VERSION 5.7 ;
  NOWIREEXTENSIONATPIN ON ;
  DIVIDERCHAR "/" ;
  BUSBITCHARS "[]" ;
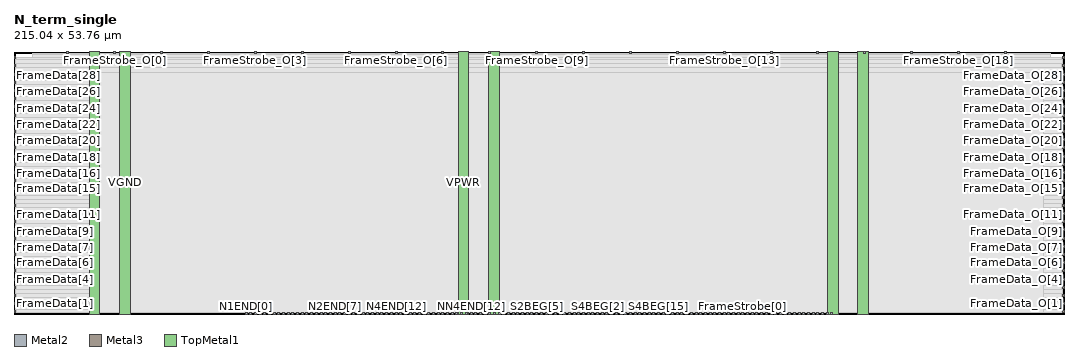
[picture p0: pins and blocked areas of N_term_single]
MACRO N_term_single
  CLASS BLOCK ;
  FOREIGN N_term_single ;
  ORIGIN 0.000 0.000 ;
  SIZE 215.040 BY 53.760 ;
  PIN Ci
    DIRECTION INPUT ;
    USE SIGNAL ;
    PORT
      LAYER Metal2 ;
        RECT 97.240 0.000 97.640 0.400 ;
    END
  END Ci
  PIN FrameData[0]
    DIRECTION INPUT ;
    USE SIGNAL ;
    ANTENNAGATEAREA 0.180700 ;
    PORT
      LAYER Metal3 ;
        RECT 0.000 0.220 0.400 0.620 ;
    END
  END FrameData[0]
  PIN FrameData[10]
    DIRECTION INPUT ;
    USE SIGNAL ;
    ANTENNAGATEAREA 0.180700 ;
    PORT
      LAYER Metal3 ;
        RECT 0.000 17.020 0.400 17.420 ;
    END
  END FrameData[10]
  PIN FrameData[11]
    DIRECTION INPUT ;
    USE SIGNAL ;
    ANTENNAGATEAREA 0.180700 ;
    PORT
      LAYER Metal3 ;
        RECT 0.000 18.700 0.400 19.100 ;
    END
  END FrameData[11]
  PIN FrameData[12]
    DIRECTION INPUT ;
    USE SIGNAL ;
    ANTENNAGATEAREA 0.180700 ;
    PORT
      LAYER Metal3 ;
        RECT 0.000 20.380 0.400 20.780 ;
    END
  END FrameData[12]
  PIN FrameData[13]
    DIRECTION INPUT ;
    USE SIGNAL ;
    ANTENNAGATEAREA 0.180700 ;
    PORT
      LAYER Metal3 ;
        RECT 0.000 22.060 0.400 22.460 ;
    END
  END FrameData[13]
  PIN FrameData[14]
    DIRECTION INPUT ;
    USE SIGNAL ;
    ANTENNAGATEAREA 0.180700 ;
    PORT
      LAYER Metal3 ;
        RECT 0.000 23.740 0.400 24.140 ;
    END
  END FrameData[14]
  PIN FrameData[15]
    DIRECTION INPUT ;
    USE SIGNAL ;
    ANTENNAGATEAREA 0.180700 ;
    PORT
      LAYER Metal3 ;
        RECT 0.000 25.420 0.400 25.820 ;
    END
  END FrameData[15]
  PIN FrameData[16]
    DIRECTION INPUT ;
    USE SIGNAL ;
    ANTENNAGATEAREA 0.180700 ;
    PORT
      LAYER Metal3 ;
        RECT 0.000 27.100 0.400 27.500 ;
    END
  END FrameData[16]
  PIN FrameData[17]
    DIRECTION INPUT ;
    USE SIGNAL ;
    ANTENNAGATEAREA 0.180700 ;
    PORT
      LAYER Metal3 ;
        RECT 0.000 28.780 0.400 29.180 ;
    END
  END FrameData[17]
  PIN FrameData[18]
    DIRECTION INPUT ;
    USE SIGNAL ;
    ANTENNAGATEAREA 0.180700 ;
    PORT
      LAYER Metal3 ;
        RECT 0.000 30.460 0.400 30.860 ;
    END
  END FrameData[18]
  PIN FrameData[19]
    DIRECTION INPUT ;
    USE SIGNAL ;
    ANTENNAGATEAREA 0.180700 ;
    PORT
      LAYER Metal3 ;
        RECT 0.000 32.140 0.400 32.540 ;
    END
  END FrameData[19]
  PIN FrameData[1]
    DIRECTION INPUT ;
    USE SIGNAL ;
    ANTENNAGATEAREA 0.180700 ;
    PORT
      LAYER Metal3 ;
        RECT 0.000 1.900 0.400 2.300 ;
    END
  END FrameData[1]
  PIN FrameData[20]
    DIRECTION INPUT ;
    USE SIGNAL ;
    ANTENNAGATEAREA 0.180700 ;
    PORT
      LAYER Metal3 ;
        RECT 0.000 33.820 0.400 34.220 ;
    END
  END FrameData[20]
  PIN FrameData[21]
    DIRECTION INPUT ;
    USE SIGNAL ;
    ANTENNAGATEAREA 0.180700 ;
    PORT
      LAYER Metal3 ;
        RECT 0.000 35.500 0.400 35.900 ;
    END
  END FrameData[21]
  PIN FrameData[22]
    DIRECTION INPUT ;
    USE SIGNAL ;
    ANTENNAGATEAREA 0.180700 ;
    PORT
      LAYER Metal3 ;
        RECT 0.000 37.180 0.400 37.580 ;
    END
  END FrameData[22]
  PIN FrameData[23]
    DIRECTION INPUT ;
    USE SIGNAL ;
    ANTENNAGATEAREA 0.180700 ;
    PORT
      LAYER Metal3 ;
        RECT 0.000 38.860 0.400 39.260 ;
    END
  END FrameData[23]
  PIN FrameData[24]
    DIRECTION INPUT ;
    USE SIGNAL ;
    ANTENNAGATEAREA 0.180700 ;
    PORT
      LAYER Metal3 ;
        RECT 0.000 40.540 0.400 40.940 ;
    END
  END FrameData[24]
  PIN FrameData[25]
    DIRECTION INPUT ;
    USE SIGNAL ;
    ANTENNAGATEAREA 0.180700 ;
    PORT
      LAYER Metal3 ;
        RECT 0.000 42.220 0.400 42.620 ;
    END
  END FrameData[25]
  PIN FrameData[26]
    DIRECTION INPUT ;
    USE SIGNAL ;
    ANTENNAGATEAREA 0.180700 ;
    PORT
      LAYER Metal3 ;
        RECT 0.000 43.900 0.400 44.300 ;
    END
  END FrameData[26]
  PIN FrameData[27]
    DIRECTION INPUT ;
    USE SIGNAL ;
    ANTENNAGATEAREA 0.180700 ;
    PORT
      LAYER Metal3 ;
        RECT 0.000 45.580 0.400 45.980 ;
    END
  END FrameData[27]
  PIN FrameData[28]
    DIRECTION INPUT ;
    USE SIGNAL ;
    ANTENNAGATEAREA 0.180700 ;
    PORT
      LAYER Metal3 ;
        RECT 0.000 47.260 0.400 47.660 ;
    END
  END FrameData[28]
  PIN FrameData[29]
    DIRECTION INPUT ;
    USE SIGNAL ;
    ANTENNAGATEAREA 0.180700 ;
    PORT
      LAYER Metal3 ;
        RECT 0.000 48.940 0.400 49.340 ;
    END
  END FrameData[29]
  PIN FrameData[2]
    DIRECTION INPUT ;
    USE SIGNAL ;
    ANTENNAGATEAREA 0.180700 ;
    PORT
      LAYER Metal3 ;
        RECT 0.000 3.580 0.400 3.980 ;
    END
  END FrameData[2]
  PIN FrameData[30]
    DIRECTION INPUT ;
    USE SIGNAL ;
    ANTENNAGATEAREA 0.180700 ;
    PORT
      LAYER Metal3 ;
        RECT 0.000 50.620 0.400 51.020 ;
    END
  END FrameData[30]
  PIN FrameData[31]
    DIRECTION INPUT ;
    USE SIGNAL ;
    ANTENNAGATEAREA 0.180700 ;
    PORT
      LAYER Metal3 ;
        RECT 0.000 52.300 0.400 52.700 ;
    END
  END FrameData[31]
  PIN FrameData[3]
    DIRECTION INPUT ;
    USE SIGNAL ;
    ANTENNAGATEAREA 0.180700 ;
    PORT
      LAYER Metal3 ;
        RECT 0.000 5.260 0.400 5.660 ;
    END
  END FrameData[3]
  PIN FrameData[4]
    DIRECTION INPUT ;
    USE SIGNAL ;
    ANTENNAGATEAREA 0.180700 ;
    PORT
      LAYER Metal3 ;
        RECT 0.000 6.940 0.400 7.340 ;
    END
  END FrameData[4]
  PIN FrameData[5]
    DIRECTION INPUT ;
    USE SIGNAL ;
    ANTENNAGATEAREA 0.180700 ;
    PORT
      LAYER Metal3 ;
        RECT 0.000 8.620 0.400 9.020 ;
    END
  END FrameData[5]
  PIN FrameData[6]
    DIRECTION INPUT ;
    USE SIGNAL ;
    ANTENNAGATEAREA 0.180700 ;
    PORT
      LAYER Metal3 ;
        RECT 0.000 10.300 0.400 10.700 ;
    END
  END FrameData[6]
  PIN FrameData[7]
    DIRECTION INPUT ;
    USE SIGNAL ;
    ANTENNAGATEAREA 0.180700 ;
    PORT
      LAYER Metal3 ;
        RECT 0.000 11.980 0.400 12.380 ;
    END
  END FrameData[7]
  PIN FrameData[8]
    DIRECTION INPUT ;
    USE SIGNAL ;
    ANTENNAGATEAREA 0.180700 ;
    PORT
      LAYER Metal3 ;
        RECT 0.000 13.660 0.400 14.060 ;
    END
  END FrameData[8]
  PIN FrameData[9]
    DIRECTION INPUT ;
    USE SIGNAL ;
    ANTENNAGATEAREA 0.180700 ;
    PORT
      LAYER Metal3 ;
        RECT 0.000 15.340 0.400 15.740 ;
    END
  END FrameData[9]
  PIN FrameData_O[0]
    DIRECTION OUTPUT ;
    USE SIGNAL ;
    ANTENNADIFFAREA 0.708600 ;
    PORT
      LAYER Metal3 ;
        RECT 214.640 0.220 215.040 0.620 ;
    END
  END FrameData_O[0]
  PIN FrameData_O[10]
    DIRECTION OUTPUT ;
    USE SIGNAL ;
    ANTENNADIFFAREA 0.708600 ;
    PORT
      LAYER Metal3 ;
        RECT 214.640 17.020 215.040 17.420 ;
    END
  END FrameData_O[10]
  PIN FrameData_O[11]
    DIRECTION OUTPUT ;
    USE SIGNAL ;
    ANTENNADIFFAREA 0.708600 ;
    PORT
      LAYER Metal3 ;
        RECT 214.640 18.700 215.040 19.100 ;
    END
  END FrameData_O[11]
  PIN FrameData_O[12]
    DIRECTION OUTPUT ;
    USE SIGNAL ;
    ANTENNADIFFAREA 0.708600 ;
    PORT
      LAYER Metal3 ;
        RECT 214.640 20.380 215.040 20.780 ;
    END
  END FrameData_O[12]
  PIN FrameData_O[13]
    DIRECTION OUTPUT ;
    USE SIGNAL ;
    ANTENNADIFFAREA 0.708600 ;
    PORT
      LAYER Metal3 ;
        RECT 214.640 22.060 215.040 22.460 ;
    END
  END FrameData_O[13]
  PIN FrameData_O[14]
    DIRECTION OUTPUT ;
    USE SIGNAL ;
    ANTENNADIFFAREA 0.708600 ;
    PORT
      LAYER Metal3 ;
        RECT 214.640 23.740 215.040 24.140 ;
    END
  END FrameData_O[14]
  PIN FrameData_O[15]
    DIRECTION OUTPUT ;
    USE SIGNAL ;
    ANTENNADIFFAREA 0.708600 ;
    PORT
      LAYER Metal3 ;
        RECT 214.640 25.420 215.040 25.820 ;
    END
  END FrameData_O[15]
  PIN FrameData_O[16]
    DIRECTION OUTPUT ;
    USE SIGNAL ;
    ANTENNADIFFAREA 0.708600 ;
    PORT
      LAYER Metal3 ;
        RECT 214.640 27.100 215.040 27.500 ;
    END
  END FrameData_O[16]
  PIN FrameData_O[17]
    DIRECTION OUTPUT ;
    USE SIGNAL ;
    ANTENNADIFFAREA 0.708600 ;
    PORT
      LAYER Metal3 ;
        RECT 214.640 28.780 215.040 29.180 ;
    END
  END FrameData_O[17]
  PIN FrameData_O[18]
    DIRECTION OUTPUT ;
    USE SIGNAL ;
    ANTENNADIFFAREA 0.708600 ;
    PORT
      LAYER Metal3 ;
        RECT 214.640 30.460 215.040 30.860 ;
    END
  END FrameData_O[18]
  PIN FrameData_O[19]
    DIRECTION OUTPUT ;
    USE SIGNAL ;
    ANTENNADIFFAREA 0.708600 ;
    PORT
      LAYER Metal3 ;
        RECT 214.640 32.140 215.040 32.540 ;
    END
  END FrameData_O[19]
  PIN FrameData_O[1]
    DIRECTION OUTPUT ;
    USE SIGNAL ;
    ANTENNADIFFAREA 0.708600 ;
    PORT
      LAYER Metal3 ;
        RECT 214.640 1.900 215.040 2.300 ;
    END
  END FrameData_O[1]
  PIN FrameData_O[20]
    DIRECTION OUTPUT ;
    USE SIGNAL ;
    ANTENNADIFFAREA 0.708600 ;
    PORT
      LAYER Metal3 ;
        RECT 214.640 33.820 215.040 34.220 ;
    END
  END FrameData_O[20]
  PIN FrameData_O[21]
    DIRECTION OUTPUT ;
    USE SIGNAL ;
    ANTENNADIFFAREA 0.708600 ;
    PORT
      LAYER Metal3 ;
        RECT 214.640 35.500 215.040 35.900 ;
    END
  END FrameData_O[21]
  PIN FrameData_O[22]
    DIRECTION OUTPUT ;
    USE SIGNAL ;
    ANTENNADIFFAREA 0.708600 ;
    PORT
      LAYER Metal3 ;
        RECT 214.640 37.180 215.040 37.580 ;
    END
  END FrameData_O[22]
  PIN FrameData_O[23]
    DIRECTION OUTPUT ;
    USE SIGNAL ;
    ANTENNADIFFAREA 0.708600 ;
    PORT
      LAYER Metal3 ;
        RECT 214.640 38.860 215.040 39.260 ;
    END
  END FrameData_O[23]
  PIN FrameData_O[24]
    DIRECTION OUTPUT ;
    USE SIGNAL ;
    ANTENNADIFFAREA 0.708600 ;
    PORT
      LAYER Metal3 ;
        RECT 214.640 40.540 215.040 40.940 ;
    END
  END FrameData_O[24]
  PIN FrameData_O[25]
    DIRECTION OUTPUT ;
    USE SIGNAL ;
    ANTENNADIFFAREA 0.708600 ;
    PORT
      LAYER Metal3 ;
        RECT 214.640 42.220 215.040 42.620 ;
    END
  END FrameData_O[25]
  PIN FrameData_O[26]
    DIRECTION OUTPUT ;
    USE SIGNAL ;
    ANTENNADIFFAREA 0.708600 ;
    PORT
      LAYER Metal3 ;
        RECT 214.640 43.900 215.040 44.300 ;
    END
  END FrameData_O[26]
  PIN FrameData_O[27]
    DIRECTION OUTPUT ;
    USE SIGNAL ;
    ANTENNADIFFAREA 0.708600 ;
    PORT
      LAYER Metal3 ;
        RECT 214.640 45.580 215.040 45.980 ;
    END
  END FrameData_O[27]
  PIN FrameData_O[28]
    DIRECTION OUTPUT ;
    USE SIGNAL ;
    ANTENNADIFFAREA 0.708600 ;
    PORT
      LAYER Metal3 ;
        RECT 214.640 47.260 215.040 47.660 ;
    END
  END FrameData_O[28]
  PIN FrameData_O[29]
    DIRECTION OUTPUT ;
    USE SIGNAL ;
    ANTENNADIFFAREA 0.708600 ;
    PORT
      LAYER Metal3 ;
        RECT 214.640 48.940 215.040 49.340 ;
    END
  END FrameData_O[29]
  PIN FrameData_O[2]
    DIRECTION OUTPUT ;
    USE SIGNAL ;
    ANTENNADIFFAREA 0.708600 ;
    PORT
      LAYER Metal3 ;
        RECT 214.640 3.580 215.040 3.980 ;
    END
  END FrameData_O[2]
  PIN FrameData_O[30]
    DIRECTION OUTPUT ;
    USE SIGNAL ;
    ANTENNADIFFAREA 0.708600 ;
    PORT
      LAYER Metal3 ;
        RECT 214.640 50.620 215.040 51.020 ;
    END
  END FrameData_O[30]
  PIN FrameData_O[31]
    DIRECTION OUTPUT ;
    USE SIGNAL ;
    ANTENNADIFFAREA 0.708600 ;
    PORT
      LAYER Metal3 ;
        RECT 214.640 52.300 215.040 52.700 ;
    END
  END FrameData_O[31]
  PIN FrameData_O[3]
    DIRECTION OUTPUT ;
    USE SIGNAL ;
    ANTENNADIFFAREA 0.708600 ;
    PORT
      LAYER Metal3 ;
        RECT 214.640 5.260 215.040 5.660 ;
    END
  END FrameData_O[3]
  PIN FrameData_O[4]
    DIRECTION OUTPUT ;
    USE SIGNAL ;
    ANTENNADIFFAREA 0.708600 ;
    PORT
      LAYER Metal3 ;
        RECT 214.640 6.940 215.040 7.340 ;
    END
  END FrameData_O[4]
  PIN FrameData_O[5]
    DIRECTION OUTPUT ;
    USE SIGNAL ;
    ANTENNADIFFAREA 0.708600 ;
    PORT
      LAYER Metal3 ;
        RECT 214.640 8.620 215.040 9.020 ;
    END
  END FrameData_O[5]
  PIN FrameData_O[6]
    DIRECTION OUTPUT ;
    USE SIGNAL ;
    ANTENNADIFFAREA 0.708600 ;
    PORT
      LAYER Metal3 ;
        RECT 214.640 10.300 215.040 10.700 ;
    END
  END FrameData_O[6]
  PIN FrameData_O[7]
    DIRECTION OUTPUT ;
    USE SIGNAL ;
    ANTENNADIFFAREA 0.708600 ;
    PORT
      LAYER Metal3 ;
        RECT 214.640 11.980 215.040 12.380 ;
    END
  END FrameData_O[7]
  PIN FrameData_O[8]
    DIRECTION OUTPUT ;
    USE SIGNAL ;
    ANTENNADIFFAREA 0.708600 ;
    PORT
      LAYER Metal3 ;
        RECT 214.640 13.660 215.040 14.060 ;
    END
  END FrameData_O[8]
  PIN FrameData_O[9]
    DIRECTION OUTPUT ;
    USE SIGNAL ;
    ANTENNADIFFAREA 0.708600 ;
    PORT
      LAYER Metal3 ;
        RECT 214.640 15.340 215.040 15.740 ;
    END
  END FrameData_O[9]
  PIN FrameStrobe[0]
    DIRECTION INPUT ;
    USE SIGNAL ;
    ANTENNAGATEAREA 0.180700 ;
    PORT
      LAYER Metal2 ;
        RECT 149.080 0.000 149.480 0.400 ;
    END
  END FrameStrobe[0]
  PIN FrameStrobe[10]
    DIRECTION INPUT ;
    USE SIGNAL ;
    ANTENNAGATEAREA 0.180700 ;
    PORT
      LAYER Metal2 ;
        RECT 158.680 0.000 159.080 0.400 ;
    END
  END FrameStrobe[10]
  PIN FrameStrobe[11]
    DIRECTION INPUT ;
    USE SIGNAL ;
    ANTENNAGATEAREA 0.180700 ;
    PORT
      LAYER Metal2 ;
        RECT 159.640 0.000 160.040 0.400 ;
    END
  END FrameStrobe[11]
  PIN FrameStrobe[12]
    DIRECTION INPUT ;
    USE SIGNAL ;
    ANTENNAGATEAREA 0.180700 ;
    PORT
      LAYER Metal2 ;
        RECT 160.600 0.000 161.000 0.400 ;
    END
  END FrameStrobe[12]
  PIN FrameStrobe[13]
    DIRECTION INPUT ;
    USE SIGNAL ;
    ANTENNAGATEAREA 0.180700 ;
    PORT
      LAYER Metal2 ;
        RECT 161.560 0.000 161.960 0.400 ;
    END
  END FrameStrobe[13]
  PIN FrameStrobe[14]
    DIRECTION INPUT ;
    USE SIGNAL ;
    ANTENNAGATEAREA 0.180700 ;
    PORT
      LAYER Metal2 ;
        RECT 162.520 0.000 162.920 0.400 ;
    END
  END FrameStrobe[14]
  PIN FrameStrobe[15]
    DIRECTION INPUT ;
    USE SIGNAL ;
    ANTENNAGATEAREA 0.180700 ;
    PORT
      LAYER Metal2 ;
        RECT 163.480 0.000 163.880 0.400 ;
    END
  END FrameStrobe[15]
  PIN FrameStrobe[16]
    DIRECTION INPUT ;
    USE SIGNAL ;
    ANTENNAGATEAREA 0.180700 ;
    PORT
      LAYER Metal2 ;
        RECT 164.440 0.000 164.840 0.400 ;
    END
  END FrameStrobe[16]
  PIN FrameStrobe[17]
    DIRECTION INPUT ;
    USE SIGNAL ;
    ANTENNAGATEAREA 0.180700 ;
    PORT
      LAYER Metal2 ;
        RECT 165.400 0.000 165.800 0.400 ;
    END
  END FrameStrobe[17]
  PIN FrameStrobe[18]
    DIRECTION INPUT ;
    USE SIGNAL ;
    ANTENNAGATEAREA 0.180700 ;
    PORT
      LAYER Metal2 ;
        RECT 166.360 0.000 166.760 0.400 ;
    END
  END FrameStrobe[18]
  PIN FrameStrobe[19]
    DIRECTION INPUT ;
    USE SIGNAL ;
    ANTENNAGATEAREA 0.180700 ;
    PORT
      LAYER Metal2 ;
        RECT 167.320 0.000 167.720 0.400 ;
    END
  END FrameStrobe[19]
  PIN FrameStrobe[1]
    DIRECTION INPUT ;
    USE SIGNAL ;
    ANTENNAGATEAREA 0.180700 ;
    PORT
      LAYER Metal2 ;
        RECT 150.040 0.000 150.440 0.400 ;
    END
  END FrameStrobe[1]
  PIN FrameStrobe[2]
    DIRECTION INPUT ;
    USE SIGNAL ;
    ANTENNAGATEAREA 0.180700 ;
    PORT
      LAYER Metal2 ;
        RECT 151.000 0.000 151.400 0.400 ;
    END
  END FrameStrobe[2]
  PIN FrameStrobe[3]
    DIRECTION INPUT ;
    USE SIGNAL ;
    ANTENNAGATEAREA 0.180700 ;
    PORT
      LAYER Metal2 ;
        RECT 151.960 0.000 152.360 0.400 ;
    END
  END FrameStrobe[3]
  PIN FrameStrobe[4]
    DIRECTION INPUT ;
    USE SIGNAL ;
    ANTENNAGATEAREA 0.180700 ;
    PORT
      LAYER Metal2 ;
        RECT 152.920 0.000 153.320 0.400 ;
    END
  END FrameStrobe[4]
  PIN FrameStrobe[5]
    DIRECTION INPUT ;
    USE SIGNAL ;
    ANTENNAGATEAREA 0.180700 ;
    PORT
      LAYER Metal2 ;
        RECT 153.880 0.000 154.280 0.400 ;
    END
  END FrameStrobe[5]
  PIN FrameStrobe[6]
    DIRECTION INPUT ;
    USE SIGNAL ;
    ANTENNAGATEAREA 0.180700 ;
    PORT
      LAYER Metal2 ;
        RECT 154.840 0.000 155.240 0.400 ;
    END
  END FrameStrobe[6]
  PIN FrameStrobe[7]
    DIRECTION INPUT ;
    USE SIGNAL ;
    ANTENNAGATEAREA 0.180700 ;
    PORT
      LAYER Metal2 ;
        RECT 155.800 0.000 156.200 0.400 ;
    END
  END FrameStrobe[7]
  PIN FrameStrobe[8]
    DIRECTION INPUT ;
    USE SIGNAL ;
    ANTENNAGATEAREA 0.180700 ;
    PORT
      LAYER Metal2 ;
        RECT 156.760 0.000 157.160 0.400 ;
    END
  END FrameStrobe[8]
  PIN FrameStrobe[9]
    DIRECTION INPUT ;
    USE SIGNAL ;
    ANTENNAGATEAREA 0.180700 ;
    PORT
      LAYER Metal2 ;
        RECT 157.720 0.000 158.120 0.400 ;
    END
  END FrameStrobe[9]
  PIN FrameStrobe_O[0]
    DIRECTION OUTPUT ;
    USE SIGNAL ;
    ANTENNADIFFAREA 0.708600 ;
    PORT
      LAYER Metal2 ;
        RECT 20.440 53.360 20.840 53.760 ;
    END
  END FrameStrobe_O[0]
  PIN FrameStrobe_O[10]
    DIRECTION OUTPUT ;
    USE SIGNAL ;
    ANTENNADIFFAREA 0.708600 ;
    PORT
      LAYER Metal2 ;
        RECT 116.440 53.360 116.840 53.760 ;
    END
  END FrameStrobe_O[10]
  PIN FrameStrobe_O[11]
    DIRECTION OUTPUT ;
    USE SIGNAL ;
    ANTENNADIFFAREA 0.708600 ;
    PORT
      LAYER Metal2 ;
        RECT 126.040 53.360 126.440 53.760 ;
    END
  END FrameStrobe_O[11]
  PIN FrameStrobe_O[12]
    DIRECTION OUTPUT ;
    USE SIGNAL ;
    ANTENNADIFFAREA 0.708600 ;
    PORT
      LAYER Metal2 ;
        RECT 135.640 53.360 136.040 53.760 ;
    END
  END FrameStrobe_O[12]
  PIN FrameStrobe_O[13]
    DIRECTION OUTPUT ;
    USE SIGNAL ;
    ANTENNADIFFAREA 0.708600 ;
    PORT
      LAYER Metal2 ;
        RECT 145.240 53.360 145.640 53.760 ;
    END
  END FrameStrobe_O[13]
  PIN FrameStrobe_O[14]
    DIRECTION OUTPUT ;
    USE SIGNAL ;
    ANTENNADIFFAREA 0.708600 ;
    PORT
      LAYER Metal2 ;
        RECT 154.840 53.360 155.240 53.760 ;
    END
  END FrameStrobe_O[14]
  PIN FrameStrobe_O[15]
    DIRECTION OUTPUT ;
    USE SIGNAL ;
    ANTENNADIFFAREA 0.708600 ;
    PORT
      LAYER Metal2 ;
        RECT 164.440 53.360 164.840 53.760 ;
    END
  END FrameStrobe_O[15]
  PIN FrameStrobe_O[16]
    DIRECTION OUTPUT ;
    USE SIGNAL ;
    ANTENNADIFFAREA 0.708600 ;
    PORT
      LAYER Metal2 ;
        RECT 174.040 53.360 174.440 53.760 ;
    END
  END FrameStrobe_O[16]
  PIN FrameStrobe_O[17]
    DIRECTION OUTPUT ;
    USE SIGNAL ;
    ANTENNADIFFAREA 0.708600 ;
    PORT
      LAYER Metal2 ;
        RECT 183.640 53.360 184.040 53.760 ;
    END
  END FrameStrobe_O[17]
  PIN FrameStrobe_O[18]
    DIRECTION OUTPUT ;
    USE SIGNAL ;
    ANTENNADIFFAREA 0.708600 ;
    PORT
      LAYER Metal2 ;
        RECT 193.240 53.360 193.640 53.760 ;
    END
  END FrameStrobe_O[18]
  PIN FrameStrobe_O[19]
    DIRECTION OUTPUT ;
    USE SIGNAL ;
    ANTENNADIFFAREA 0.708600 ;
    PORT
      LAYER Metal2 ;
        RECT 202.840 53.360 203.240 53.760 ;
    END
  END FrameStrobe_O[19]
  PIN FrameStrobe_O[1]
    DIRECTION OUTPUT ;
    USE SIGNAL ;
    ANTENNADIFFAREA 0.708600 ;
    PORT
      LAYER Metal2 ;
        RECT 30.040 53.360 30.440 53.760 ;
    END
  END FrameStrobe_O[1]
  PIN FrameStrobe_O[2]
    DIRECTION OUTPUT ;
    USE SIGNAL ;
    ANTENNADIFFAREA 0.708600 ;
    PORT
      LAYER Metal2 ;
        RECT 39.640 53.360 40.040 53.760 ;
    END
  END FrameStrobe_O[2]
  PIN FrameStrobe_O[3]
    DIRECTION OUTPUT ;
    USE SIGNAL ;
    ANTENNADIFFAREA 0.708600 ;
    PORT
      LAYER Metal2 ;
        RECT 49.240 53.360 49.640 53.760 ;
    END
  END FrameStrobe_O[3]
  PIN FrameStrobe_O[4]
    DIRECTION OUTPUT ;
    USE SIGNAL ;
    ANTENNADIFFAREA 0.708600 ;
    PORT
      LAYER Metal2 ;
        RECT 58.840 53.360 59.240 53.760 ;
    END
  END FrameStrobe_O[4]
  PIN FrameStrobe_O[5]
    DIRECTION OUTPUT ;
    USE SIGNAL ;
    ANTENNADIFFAREA 0.708600 ;
    PORT
      LAYER Metal2 ;
        RECT 68.440 53.360 68.840 53.760 ;
    END
  END FrameStrobe_O[5]
  PIN FrameStrobe_O[6]
    DIRECTION OUTPUT ;
    USE SIGNAL ;
    ANTENNADIFFAREA 0.708600 ;
    PORT
      LAYER Metal2 ;
        RECT 78.040 53.360 78.440 53.760 ;
    END
  END FrameStrobe_O[6]
  PIN FrameStrobe_O[7]
    DIRECTION OUTPUT ;
    USE SIGNAL ;
    ANTENNADIFFAREA 0.708600 ;
    PORT
      LAYER Metal2 ;
        RECT 87.640 53.360 88.040 53.760 ;
    END
  END FrameStrobe_O[7]
  PIN FrameStrobe_O[8]
    DIRECTION OUTPUT ;
    USE SIGNAL ;
    ANTENNADIFFAREA 0.708600 ;
    PORT
      LAYER Metal2 ;
        RECT 97.240 53.360 97.640 53.760 ;
    END
  END FrameStrobe_O[8]
  PIN FrameStrobe_O[9]
    DIRECTION OUTPUT ;
    USE SIGNAL ;
    ANTENNADIFFAREA 0.708600 ;
    PORT
      LAYER Metal2 ;
        RECT 106.840 53.360 107.240 53.760 ;
    END
  END FrameStrobe_O[9]
  PIN N1END[0]
    DIRECTION INPUT ;
    USE SIGNAL ;
    ANTENNAGATEAREA 0.180700 ;
    PORT
      LAYER Metal2 ;
        RECT 47.320 0.000 47.720 0.400 ;
    END
  END N1END[0]
  PIN N1END[1]
    DIRECTION INPUT ;
    USE SIGNAL ;
    ANTENNAGATEAREA 0.180700 ;
    PORT
      LAYER Metal2 ;
        RECT 48.280 0.000 48.680 0.400 ;
    END
  END N1END[1]
  PIN N1END[2]
    DIRECTION INPUT ;
    USE SIGNAL ;
    ANTENNAGATEAREA 0.180700 ;
    PORT
      LAYER Metal2 ;
        RECT 49.240 0.000 49.640 0.400 ;
    END
  END N1END[2]
  PIN N1END[3]
    DIRECTION INPUT ;
    USE SIGNAL ;
    ANTENNAGATEAREA 0.180700 ;
    PORT
      LAYER Metal2 ;
        RECT 50.200 0.000 50.600 0.400 ;
    END
  END N1END[3]
  PIN N2END[0]
    DIRECTION INPUT ;
    USE SIGNAL ;
    ANTENNAGATEAREA 0.180700 ;
    PORT
      LAYER Metal2 ;
        RECT 58.840 0.000 59.240 0.400 ;
    END
  END N2END[0]
  PIN N2END[1]
    DIRECTION INPUT ;
    USE SIGNAL ;
    ANTENNAGATEAREA 0.180700 ;
    PORT
      LAYER Metal2 ;
        RECT 59.800 0.000 60.200 0.400 ;
    END
  END N2END[1]
  PIN N2END[2]
    DIRECTION INPUT ;
    USE SIGNAL ;
    ANTENNAGATEAREA 0.180700 ;
    PORT
      LAYER Metal2 ;
        RECT 60.760 0.000 61.160 0.400 ;
    END
  END N2END[2]
  PIN N2END[3]
    DIRECTION INPUT ;
    USE SIGNAL ;
    ANTENNAGATEAREA 0.180700 ;
    PORT
      LAYER Metal2 ;
        RECT 61.720 0.000 62.120 0.400 ;
    END
  END N2END[3]
  PIN N2END[4]
    DIRECTION INPUT ;
    USE SIGNAL ;
    ANTENNAGATEAREA 0.180700 ;
    PORT
      LAYER Metal2 ;
        RECT 62.680 0.000 63.080 0.400 ;
    END
  END N2END[4]
  PIN N2END[5]
    DIRECTION INPUT ;
    USE SIGNAL ;
    ANTENNAGATEAREA 0.180700 ;
    PORT
      LAYER Metal2 ;
        RECT 63.640 0.000 64.040 0.400 ;
    END
  END N2END[5]
  PIN N2END[6]
    DIRECTION INPUT ;
    USE SIGNAL ;
    ANTENNAGATEAREA 0.180700 ;
    PORT
      LAYER Metal2 ;
        RECT 64.600 0.000 65.000 0.400 ;
    END
  END N2END[6]
  PIN N2END[7]
    DIRECTION INPUT ;
    USE SIGNAL ;
    ANTENNAGATEAREA 0.180700 ;
    PORT
      LAYER Metal2 ;
        RECT 65.560 0.000 65.960 0.400 ;
    END
  END N2END[7]
  PIN N2MID[0]
    DIRECTION INPUT ;
    USE SIGNAL ;
    ANTENNAGATEAREA 0.180700 ;
    PORT
      LAYER Metal2 ;
        RECT 51.160 0.000 51.560 0.400 ;
    END
  END N2MID[0]
  PIN N2MID[1]
    DIRECTION INPUT ;
    USE SIGNAL ;
    ANTENNAGATEAREA 0.180700 ;
    PORT
      LAYER Metal2 ;
        RECT 52.120 0.000 52.520 0.400 ;
    END
  END N2MID[1]
  PIN N2MID[2]
    DIRECTION INPUT ;
    USE SIGNAL ;
    ANTENNAGATEAREA 0.180700 ;
    PORT
      LAYER Metal2 ;
        RECT 53.080 0.000 53.480 0.400 ;
    END
  END N2MID[2]
  PIN N2MID[3]
    DIRECTION INPUT ;
    USE SIGNAL ;
    ANTENNAGATEAREA 0.180700 ;
    PORT
      LAYER Metal2 ;
        RECT 54.040 0.000 54.440 0.400 ;
    END
  END N2MID[3]
  PIN N2MID[4]
    DIRECTION INPUT ;
    USE SIGNAL ;
    ANTENNAGATEAREA 0.180700 ;
    PORT
      LAYER Metal2 ;
        RECT 55.000 0.000 55.400 0.400 ;
    END
  END N2MID[4]
  PIN N2MID[5]
    DIRECTION INPUT ;
    USE SIGNAL ;
    ANTENNAGATEAREA 0.180700 ;
    PORT
      LAYER Metal2 ;
        RECT 55.960 0.000 56.360 0.400 ;
    END
  END N2MID[5]
  PIN N2MID[6]
    DIRECTION INPUT ;
    USE SIGNAL ;
    ANTENNAGATEAREA 0.180700 ;
    PORT
      LAYER Metal2 ;
        RECT 56.920 0.000 57.320 0.400 ;
    END
  END N2MID[6]
  PIN N2MID[7]
    DIRECTION INPUT ;
    USE SIGNAL ;
    ANTENNAGATEAREA 0.180700 ;
    PORT
      LAYER Metal2 ;
        RECT 57.880 0.000 58.280 0.400 ;
    END
  END N2MID[7]
  PIN N4END[0]
    DIRECTION INPUT ;
    USE SIGNAL ;
    ANTENNAGATEAREA 0.180700 ;
    PORT
      LAYER Metal2 ;
        RECT 66.520 0.000 66.920 0.400 ;
    END
  END N4END[0]
  PIN N4END[10]
    DIRECTION INPUT ;
    USE SIGNAL ;
    ANTENNAGATEAREA 0.180700 ;
    PORT
      LAYER Metal2 ;
        RECT 76.120 0.000 76.520 0.400 ;
    END
  END N4END[10]
  PIN N4END[11]
    DIRECTION INPUT ;
    USE SIGNAL ;
    ANTENNAGATEAREA 0.180700 ;
    PORT
      LAYER Metal2 ;
        RECT 77.080 0.000 77.480 0.400 ;
    END
  END N4END[11]
  PIN N4END[12]
    DIRECTION INPUT ;
    USE SIGNAL ;
    ANTENNAGATEAREA 0.180700 ;
    PORT
      LAYER Metal2 ;
        RECT 78.040 0.000 78.440 0.400 ;
    END
  END N4END[12]
  PIN N4END[13]
    DIRECTION INPUT ;
    USE SIGNAL ;
    ANTENNAGATEAREA 0.180700 ;
    PORT
      LAYER Metal2 ;
        RECT 79.000 0.000 79.400 0.400 ;
    END
  END N4END[13]
  PIN N4END[14]
    DIRECTION INPUT ;
    USE SIGNAL ;
    ANTENNAGATEAREA 0.180700 ;
    PORT
      LAYER Metal2 ;
        RECT 79.960 0.000 80.360 0.400 ;
    END
  END N4END[14]
  PIN N4END[15]
    DIRECTION INPUT ;
    USE SIGNAL ;
    ANTENNAGATEAREA 0.180700 ;
    PORT
      LAYER Metal2 ;
        RECT 80.920 0.000 81.320 0.400 ;
    END
  END N4END[15]
  PIN N4END[1]
    DIRECTION INPUT ;
    USE SIGNAL ;
    ANTENNAGATEAREA 0.180700 ;
    PORT
      LAYER Metal2 ;
        RECT 67.480 0.000 67.880 0.400 ;
    END
  END N4END[1]
  PIN N4END[2]
    DIRECTION INPUT ;
    USE SIGNAL ;
    ANTENNAGATEAREA 0.180700 ;
    PORT
      LAYER Metal2 ;
        RECT 68.440 0.000 68.840 0.400 ;
    END
  END N4END[2]
  PIN N4END[3]
    DIRECTION INPUT ;
    USE SIGNAL ;
    ANTENNAGATEAREA 0.180700 ;
    PORT
      LAYER Metal2 ;
        RECT 69.400 0.000 69.800 0.400 ;
    END
  END N4END[3]
  PIN N4END[4]
    DIRECTION INPUT ;
    USE SIGNAL ;
    ANTENNAGATEAREA 0.180700 ;
    PORT
      LAYER Metal2 ;
        RECT 70.360 0.000 70.760 0.400 ;
    END
  END N4END[4]
  PIN N4END[5]
    DIRECTION INPUT ;
    USE SIGNAL ;
    ANTENNAGATEAREA 0.180700 ;
    PORT
      LAYER Metal2 ;
        RECT 71.320 0.000 71.720 0.400 ;
    END
  END N4END[5]
  PIN N4END[6]
    DIRECTION INPUT ;
    USE SIGNAL ;
    ANTENNAGATEAREA 0.180700 ;
    PORT
      LAYER Metal2 ;
        RECT 72.280 0.000 72.680 0.400 ;
    END
  END N4END[6]
  PIN N4END[7]
    DIRECTION INPUT ;
    USE SIGNAL ;
    ANTENNAGATEAREA 0.180700 ;
    PORT
      LAYER Metal2 ;
        RECT 73.240 0.000 73.640 0.400 ;
    END
  END N4END[7]
  PIN N4END[8]
    DIRECTION INPUT ;
    USE SIGNAL ;
    ANTENNAGATEAREA 0.180700 ;
    PORT
      LAYER Metal2 ;
        RECT 74.200 0.000 74.600 0.400 ;
    END
  END N4END[8]
  PIN N4END[9]
    DIRECTION INPUT ;
    USE SIGNAL ;
    ANTENNAGATEAREA 0.180700 ;
    PORT
      LAYER Metal2 ;
        RECT 75.160 0.000 75.560 0.400 ;
    END
  END N4END[9]
  PIN NN4END[0]
    DIRECTION INPUT ;
    USE SIGNAL ;
    ANTENNAGATEAREA 0.180700 ;
    PORT
      LAYER Metal2 ;
        RECT 81.880 0.000 82.280 0.400 ;
    END
  END NN4END[0]
  PIN NN4END[10]
    DIRECTION INPUT ;
    USE SIGNAL ;
    ANTENNAGATEAREA 0.180700 ;
    PORT
      LAYER Metal2 ;
        RECT 91.480 0.000 91.880 0.400 ;
    END
  END NN4END[10]
  PIN NN4END[11]
    DIRECTION INPUT ;
    USE SIGNAL ;
    ANTENNAGATEAREA 0.180700 ;
    PORT
      LAYER Metal2 ;
        RECT 92.440 0.000 92.840 0.400 ;
    END
  END NN4END[11]
  PIN NN4END[12]
    DIRECTION INPUT ;
    USE SIGNAL ;
    ANTENNAGATEAREA 0.180700 ;
    PORT
      LAYER Metal2 ;
        RECT 93.400 0.000 93.800 0.400 ;
    END
  END NN4END[12]
  PIN NN4END[13]
    DIRECTION INPUT ;
    USE SIGNAL ;
    ANTENNAGATEAREA 0.180700 ;
    PORT
      LAYER Metal2 ;
        RECT 94.360 0.000 94.760 0.400 ;
    END
  END NN4END[13]
  PIN NN4END[14]
    DIRECTION INPUT ;
    USE SIGNAL ;
    ANTENNAGATEAREA 0.180700 ;
    PORT
      LAYER Metal2 ;
        RECT 95.320 0.000 95.720 0.400 ;
    END
  END NN4END[14]
  PIN NN4END[15]
    DIRECTION INPUT ;
    USE SIGNAL ;
    ANTENNAGATEAREA 0.180700 ;
    PORT
      LAYER Metal2 ;
        RECT 96.280 0.000 96.680 0.400 ;
    END
  END NN4END[15]
  PIN NN4END[1]
    DIRECTION INPUT ;
    USE SIGNAL ;
    ANTENNAGATEAREA 0.180700 ;
    PORT
      LAYER Metal2 ;
        RECT 82.840 0.000 83.240 0.400 ;
    END
  END NN4END[1]
  PIN NN4END[2]
    DIRECTION INPUT ;
    USE SIGNAL ;
    ANTENNAGATEAREA 0.180700 ;
    PORT
      LAYER Metal2 ;
        RECT 83.800 0.000 84.200 0.400 ;
    END
  END NN4END[2]
  PIN NN4END[3]
    DIRECTION INPUT ;
    USE SIGNAL ;
    ANTENNAGATEAREA 0.180700 ;
    PORT
      LAYER Metal2 ;
        RECT 84.760 0.000 85.160 0.400 ;
    END
  END NN4END[3]
  PIN NN4END[4]
    DIRECTION INPUT ;
    USE SIGNAL ;
    ANTENNAGATEAREA 0.180700 ;
    PORT
      LAYER Metal2 ;
        RECT 85.720 0.000 86.120 0.400 ;
    END
  END NN4END[4]
  PIN NN4END[5]
    DIRECTION INPUT ;
    USE SIGNAL ;
    ANTENNAGATEAREA 0.180700 ;
    PORT
      LAYER Metal2 ;
        RECT 86.680 0.000 87.080 0.400 ;
    END
  END NN4END[5]
  PIN NN4END[6]
    DIRECTION INPUT ;
    USE SIGNAL ;
    ANTENNAGATEAREA 0.180700 ;
    PORT
      LAYER Metal2 ;
        RECT 87.640 0.000 88.040 0.400 ;
    END
  END NN4END[6]
  PIN NN4END[7]
    DIRECTION INPUT ;
    USE SIGNAL ;
    ANTENNAGATEAREA 0.180700 ;
    PORT
      LAYER Metal2 ;
        RECT 88.600 0.000 89.000 0.400 ;
    END
  END NN4END[7]
  PIN NN4END[8]
    DIRECTION INPUT ;
    USE SIGNAL ;
    ANTENNAGATEAREA 0.180700 ;
    PORT
      LAYER Metal2 ;
        RECT 89.560 0.000 89.960 0.400 ;
    END
  END NN4END[8]
  PIN NN4END[9]
    DIRECTION INPUT ;
    USE SIGNAL ;
    ANTENNAGATEAREA 0.180700 ;
    PORT
      LAYER Metal2 ;
        RECT 90.520 0.000 90.920 0.400 ;
    END
  END NN4END[9]
  PIN S1BEG[0]
    DIRECTION OUTPUT ;
    USE SIGNAL ;
    ANTENNADIFFAREA 0.708600 ;
    PORT
      LAYER Metal2 ;
        RECT 98.200 0.000 98.600 0.400 ;
    END
  END S1BEG[0]
  PIN S1BEG[1]
    DIRECTION OUTPUT ;
    USE SIGNAL ;
    ANTENNADIFFAREA 0.708600 ;
    PORT
      LAYER Metal2 ;
        RECT 99.160 0.000 99.560 0.400 ;
    END
  END S1BEG[1]
  PIN S1BEG[2]
    DIRECTION OUTPUT ;
    USE SIGNAL ;
    ANTENNADIFFAREA 0.708600 ;
    PORT
      LAYER Metal2 ;
        RECT 100.120 0.000 100.520 0.400 ;
    END
  END S1BEG[2]
  PIN S1BEG[3]
    DIRECTION OUTPUT ;
    USE SIGNAL ;
    ANTENNADIFFAREA 0.708600 ;
    PORT
      LAYER Metal2 ;
        RECT 101.080 0.000 101.480 0.400 ;
    END
  END S1BEG[3]
  PIN S2BEG[0]
    DIRECTION OUTPUT ;
    USE SIGNAL ;
    ANTENNADIFFAREA 0.708600 ;
    PORT
      LAYER Metal2 ;
        RECT 102.040 0.000 102.440 0.400 ;
    END
  END S2BEG[0]
  PIN S2BEG[1]
    DIRECTION OUTPUT ;
    USE SIGNAL ;
    ANTENNADIFFAREA 0.708600 ;
    PORT
      LAYER Metal2 ;
        RECT 103.000 0.000 103.400 0.400 ;
    END
  END S2BEG[1]
  PIN S2BEG[2]
    DIRECTION OUTPUT ;
    USE SIGNAL ;
    ANTENNADIFFAREA 0.708600 ;
    PORT
      LAYER Metal2 ;
        RECT 103.960 0.000 104.360 0.400 ;
    END
  END S2BEG[2]
  PIN S2BEG[3]
    DIRECTION OUTPUT ;
    USE SIGNAL ;
    ANTENNADIFFAREA 0.708600 ;
    PORT
      LAYER Metal2 ;
        RECT 104.920 0.000 105.320 0.400 ;
    END
  END S2BEG[3]
  PIN S2BEG[4]
    DIRECTION OUTPUT ;
    USE SIGNAL ;
    ANTENNADIFFAREA 0.708600 ;
    PORT
      LAYER Metal2 ;
        RECT 105.880 0.000 106.280 0.400 ;
    END
  END S2BEG[4]
  PIN S2BEG[5]
    DIRECTION OUTPUT ;
    USE SIGNAL ;
    ANTENNADIFFAREA 0.708600 ;
    PORT
      LAYER Metal2 ;
        RECT 106.840 0.000 107.240 0.400 ;
    END
  END S2BEG[5]
  PIN S2BEG[6]
    DIRECTION OUTPUT ;
    USE SIGNAL ;
    ANTENNADIFFAREA 0.708600 ;
    PORT
      LAYER Metal2 ;
        RECT 107.800 0.000 108.200 0.400 ;
    END
  END S2BEG[6]
  PIN S2BEG[7]
    DIRECTION OUTPUT ;
    USE SIGNAL ;
    ANTENNADIFFAREA 0.708600 ;
    PORT
      LAYER Metal2 ;
        RECT 108.760 0.000 109.160 0.400 ;
    END
  END S2BEG[7]
  PIN S2BEGb[0]
    DIRECTION OUTPUT ;
    USE SIGNAL ;
    ANTENNADIFFAREA 0.708600 ;
    PORT
      LAYER Metal2 ;
        RECT 109.720 0.000 110.120 0.400 ;
    END
  END S2BEGb[0]
  PIN S2BEGb[1]
    DIRECTION OUTPUT ;
    USE SIGNAL ;
    ANTENNADIFFAREA 0.708600 ;
    PORT
      LAYER Metal2 ;
        RECT 110.680 0.000 111.080 0.400 ;
    END
  END S2BEGb[1]
  PIN S2BEGb[2]
    DIRECTION OUTPUT ;
    USE SIGNAL ;
    ANTENNADIFFAREA 0.708600 ;
    PORT
      LAYER Metal2 ;
        RECT 111.640 0.000 112.040 0.400 ;
    END
  END S2BEGb[2]
  PIN S2BEGb[3]
    DIRECTION OUTPUT ;
    USE SIGNAL ;
    ANTENNADIFFAREA 0.708600 ;
    PORT
      LAYER Metal2 ;
        RECT 112.600 0.000 113.000 0.400 ;
    END
  END S2BEGb[3]
  PIN S2BEGb[4]
    DIRECTION OUTPUT ;
    USE SIGNAL ;
    ANTENNADIFFAREA 0.708600 ;
    PORT
      LAYER Metal2 ;
        RECT 113.560 0.000 113.960 0.400 ;
    END
  END S2BEGb[4]
  PIN S2BEGb[5]
    DIRECTION OUTPUT ;
    USE SIGNAL ;
    ANTENNADIFFAREA 0.708600 ;
    PORT
      LAYER Metal2 ;
        RECT 114.520 0.000 114.920 0.400 ;
    END
  END S2BEGb[5]
  PIN S2BEGb[6]
    DIRECTION OUTPUT ;
    USE SIGNAL ;
    ANTENNADIFFAREA 0.708600 ;
    PORT
      LAYER Metal2 ;
        RECT 115.480 0.000 115.880 0.400 ;
    END
  END S2BEGb[6]
  PIN S2BEGb[7]
    DIRECTION OUTPUT ;
    USE SIGNAL ;
    ANTENNADIFFAREA 0.708600 ;
    PORT
      LAYER Metal2 ;
        RECT 116.440 0.000 116.840 0.400 ;
    END
  END S2BEGb[7]
  PIN S4BEG[0]
    DIRECTION OUTPUT ;
    USE SIGNAL ;
    ANTENNADIFFAREA 0.708600 ;
    PORT
      LAYER Metal2 ;
        RECT 117.400 0.000 117.800 0.400 ;
    END
  END S4BEG[0]
  PIN S4BEG[10]
    DIRECTION OUTPUT ;
    USE SIGNAL ;
    ANTENNADIFFAREA 0.708600 ;
    PORT
      LAYER Metal2 ;
        RECT 127.000 0.000 127.400 0.400 ;
    END
  END S4BEG[10]
  PIN S4BEG[11]
    DIRECTION OUTPUT ;
    USE SIGNAL ;
    ANTENNADIFFAREA 0.708600 ;
    PORT
      LAYER Metal2 ;
        RECT 127.960 0.000 128.360 0.400 ;
    END
  END S4BEG[11]
  PIN S4BEG[12]
    DIRECTION OUTPUT ;
    USE SIGNAL ;
    ANTENNADIFFAREA 0.708600 ;
    PORT
      LAYER Metal2 ;
        RECT 128.920 0.000 129.320 0.400 ;
    END
  END S4BEG[12]
  PIN S4BEG[13]
    DIRECTION OUTPUT ;
    USE SIGNAL ;
    ANTENNADIFFAREA 0.708600 ;
    PORT
      LAYER Metal2 ;
        RECT 129.880 0.000 130.280 0.400 ;
    END
  END S4BEG[13]
  PIN S4BEG[14]
    DIRECTION OUTPUT ;
    USE SIGNAL ;
    ANTENNADIFFAREA 0.708600 ;
    PORT
      LAYER Metal2 ;
        RECT 130.840 0.000 131.240 0.400 ;
    END
  END S4BEG[14]
  PIN S4BEG[15]
    DIRECTION OUTPUT ;
    USE SIGNAL ;
    ANTENNADIFFAREA 0.708600 ;
    PORT
      LAYER Metal2 ;
        RECT 131.800 0.000 132.200 0.400 ;
    END
  END S4BEG[15]
  PIN S4BEG[1]
    DIRECTION OUTPUT ;
    USE SIGNAL ;
    ANTENNADIFFAREA 0.708600 ;
    PORT
      LAYER Metal2 ;
        RECT 118.360 0.000 118.760 0.400 ;
    END
  END S4BEG[1]
  PIN S4BEG[2]
    DIRECTION OUTPUT ;
    USE SIGNAL ;
    ANTENNADIFFAREA 0.708600 ;
    PORT
      LAYER Metal2 ;
        RECT 119.320 0.000 119.720 0.400 ;
    END
  END S4BEG[2]
  PIN S4BEG[3]
    DIRECTION OUTPUT ;
    USE SIGNAL ;
    ANTENNADIFFAREA 0.708600 ;
    PORT
      LAYER Metal2 ;
        RECT 120.280 0.000 120.680 0.400 ;
    END
  END S4BEG[3]
  PIN S4BEG[4]
    DIRECTION OUTPUT ;
    USE SIGNAL ;
    ANTENNADIFFAREA 0.708600 ;
    PORT
      LAYER Metal2 ;
        RECT 121.240 0.000 121.640 0.400 ;
    END
  END S4BEG[4]
  PIN S4BEG[5]
    DIRECTION OUTPUT ;
    USE SIGNAL ;
    ANTENNADIFFAREA 0.708600 ;
    PORT
      LAYER Metal2 ;
        RECT 122.200 0.000 122.600 0.400 ;
    END
  END S4BEG[5]
  PIN S4BEG[6]
    DIRECTION OUTPUT ;
    USE SIGNAL ;
    ANTENNADIFFAREA 0.708600 ;
    PORT
      LAYER Metal2 ;
        RECT 123.160 0.000 123.560 0.400 ;
    END
  END S4BEG[6]
  PIN S4BEG[7]
    DIRECTION OUTPUT ;
    USE SIGNAL ;
    ANTENNADIFFAREA 0.708600 ;
    PORT
      LAYER Metal2 ;
        RECT 124.120 0.000 124.520 0.400 ;
    END
  END S4BEG[7]
  PIN S4BEG[8]
    DIRECTION OUTPUT ;
    USE SIGNAL ;
    ANTENNADIFFAREA 0.708600 ;
    PORT
      LAYER Metal2 ;
        RECT 125.080 0.000 125.480 0.400 ;
    END
  END S4BEG[8]
  PIN S4BEG[9]
    DIRECTION OUTPUT ;
    USE SIGNAL ;
    ANTENNADIFFAREA 0.708600 ;
    PORT
      LAYER Metal2 ;
        RECT 126.040 0.000 126.440 0.400 ;
    END
  END S4BEG[9]
  PIN SS4BEG[0]
    DIRECTION OUTPUT ;
    USE SIGNAL ;
    ANTENNADIFFAREA 0.708600 ;
    PORT
      LAYER Metal2 ;
        RECT 132.760 0.000 133.160 0.400 ;
    END
  END SS4BEG[0]
  PIN SS4BEG[10]
    DIRECTION OUTPUT ;
    USE SIGNAL ;
    ANTENNADIFFAREA 0.708600 ;
    PORT
      LAYER Metal2 ;
        RECT 142.360 0.000 142.760 0.400 ;
    END
  END SS4BEG[10]
  PIN SS4BEG[11]
    DIRECTION OUTPUT ;
    USE SIGNAL ;
    ANTENNADIFFAREA 0.708600 ;
    PORT
      LAYER Metal2 ;
        RECT 143.320 0.000 143.720 0.400 ;
    END
  END SS4BEG[11]
  PIN SS4BEG[12]
    DIRECTION OUTPUT ;
    USE SIGNAL ;
    ANTENNADIFFAREA 0.708600 ;
    PORT
      LAYER Metal2 ;
        RECT 144.280 0.000 144.680 0.400 ;
    END
  END SS4BEG[12]
  PIN SS4BEG[13]
    DIRECTION OUTPUT ;
    USE SIGNAL ;
    ANTENNADIFFAREA 0.708600 ;
    PORT
      LAYER Metal2 ;
        RECT 145.240 0.000 145.640 0.400 ;
    END
  END SS4BEG[13]
  PIN SS4BEG[14]
    DIRECTION OUTPUT ;
    USE SIGNAL ;
    ANTENNADIFFAREA 0.708600 ;
    PORT
      LAYER Metal2 ;
        RECT 146.200 0.000 146.600 0.400 ;
    END
  END SS4BEG[14]
  PIN SS4BEG[15]
    DIRECTION OUTPUT ;
    USE SIGNAL ;
    ANTENNADIFFAREA 0.708600 ;
    PORT
      LAYER Metal2 ;
        RECT 147.160 0.000 147.560 0.400 ;
    END
  END SS4BEG[15]
  PIN SS4BEG[1]
    DIRECTION OUTPUT ;
    USE SIGNAL ;
    ANTENNADIFFAREA 0.708600 ;
    PORT
      LAYER Metal2 ;
        RECT 133.720 0.000 134.120 0.400 ;
    END
  END SS4BEG[1]
  PIN SS4BEG[2]
    DIRECTION OUTPUT ;
    USE SIGNAL ;
    ANTENNADIFFAREA 0.708600 ;
    PORT
      LAYER Metal2 ;
        RECT 134.680 0.000 135.080 0.400 ;
    END
  END SS4BEG[2]
  PIN SS4BEG[3]
    DIRECTION OUTPUT ;
    USE SIGNAL ;
    ANTENNADIFFAREA 0.708600 ;
    PORT
      LAYER Metal2 ;
        RECT 135.640 0.000 136.040 0.400 ;
    END
  END SS4BEG[3]
  PIN SS4BEG[4]
    DIRECTION OUTPUT ;
    USE SIGNAL ;
    ANTENNADIFFAREA 0.708600 ;
    PORT
      LAYER Metal2 ;
        RECT 136.600 0.000 137.000 0.400 ;
    END
  END SS4BEG[4]
  PIN SS4BEG[5]
    DIRECTION OUTPUT ;
    USE SIGNAL ;
    ANTENNADIFFAREA 0.708600 ;
    PORT
      LAYER Metal2 ;
        RECT 137.560 0.000 137.960 0.400 ;
    END
  END SS4BEG[5]
  PIN SS4BEG[6]
    DIRECTION OUTPUT ;
    USE SIGNAL ;
    ANTENNADIFFAREA 0.708600 ;
    PORT
      LAYER Metal2 ;
        RECT 138.520 0.000 138.920 0.400 ;
    END
  END SS4BEG[6]
  PIN SS4BEG[7]
    DIRECTION OUTPUT ;
    USE SIGNAL ;
    ANTENNADIFFAREA 0.708600 ;
    PORT
      LAYER Metal2 ;
        RECT 139.480 0.000 139.880 0.400 ;
    END
  END SS4BEG[7]
  PIN SS4BEG[8]
    DIRECTION OUTPUT ;
    USE SIGNAL ;
    ANTENNADIFFAREA 0.708600 ;
    PORT
      LAYER Metal2 ;
        RECT 140.440 0.000 140.840 0.400 ;
    END
  END SS4BEG[8]
  PIN SS4BEG[9]
    DIRECTION OUTPUT ;
    USE SIGNAL ;
    ANTENNADIFFAREA 0.708600 ;
    PORT
      LAYER Metal2 ;
        RECT 141.400 0.000 141.800 0.400 ;
    END
  END SS4BEG[9]
  PIN UserCLK
    DIRECTION INPUT ;
    USE SIGNAL ;
    ANTENNAGATEAREA 0.180700 ;
    PORT
      LAYER Metal2 ;
        RECT 148.120 0.000 148.520 0.400 ;
    END
  END UserCLK
  PIN UserCLKo
    DIRECTION OUTPUT ;
    USE SIGNAL ;
    ANTENNADIFFAREA 0.708600 ;
    PORT
      LAYER Metal2 ;
        RECT 10.840 53.360 11.240 53.760 ;
    END
  END UserCLKo
  PIN VGND
    DIRECTION INOUT ;
    USE GROUND ;
    PORT
      LAYER TopMetal1 ;
        RECT 21.580 0.000 23.780 53.760 ;
    END
    PORT
      LAYER TopMetal1 ;
        RECT 97.180 0.000 99.380 53.760 ;
    END
    PORT
      LAYER TopMetal1 ;
        RECT 172.780 0.000 174.980 53.760 ;
    END
  END VGND
  PIN VPWR
    DIRECTION INOUT ;
    USE POWER ;
    PORT
      LAYER TopMetal1 ;
        RECT 15.380 0.000 17.580 53.760 ;
    END
    PORT
      LAYER TopMetal1 ;
        RECT 90.980 0.000 93.180 53.760 ;
    END
    PORT
      LAYER TopMetal1 ;
        RECT 166.580 0.000 168.780 53.760 ;
    END
  END VPWR
  OBS
      LAYER GatPoly ;
        RECT 2.880 3.630 212.160 49.290 ;
      LAYER Metal1 ;
        RECT 2.880 3.560 212.160 49.360 ;
      LAYER Metal2 ;
        RECT 3.735 53.150 10.630 53.360 ;
        RECT 11.450 53.150 20.230 53.360 ;
        RECT 21.050 53.150 29.830 53.360 ;
        RECT 30.650 53.150 39.430 53.360 ;
        RECT 40.250 53.150 49.030 53.360 ;
        RECT 49.850 53.150 58.630 53.360 ;
        RECT 59.450 53.150 68.230 53.360 ;
        RECT 69.050 53.150 77.830 53.360 ;
        RECT 78.650 53.150 87.430 53.360 ;
        RECT 88.250 53.150 97.030 53.360 ;
        RECT 97.850 53.150 106.630 53.360 ;
        RECT 107.450 53.150 116.230 53.360 ;
        RECT 117.050 53.150 125.830 53.360 ;
        RECT 126.650 53.150 135.430 53.360 ;
        RECT 136.250 53.150 145.030 53.360 ;
        RECT 145.850 53.150 154.630 53.360 ;
        RECT 155.450 53.150 164.230 53.360 ;
        RECT 165.050 53.150 173.830 53.360 ;
        RECT 174.650 53.150 183.430 53.360 ;
        RECT 184.250 53.150 193.030 53.360 ;
        RECT 193.850 53.150 202.630 53.360 ;
        RECT 203.450 53.150 212.265 53.360 ;
        RECT 3.735 0.610 212.265 53.150 ;
        RECT 3.735 0.275 47.110 0.610 ;
        RECT 47.930 0.275 48.070 0.610 ;
        RECT 48.890 0.275 49.030 0.610 ;
        RECT 49.850 0.275 49.990 0.610 ;
        RECT 50.810 0.275 50.950 0.610 ;
        RECT 51.770 0.275 51.910 0.610 ;
        RECT 52.730 0.275 52.870 0.610 ;
        RECT 53.690 0.275 53.830 0.610 ;
        RECT 54.650 0.275 54.790 0.610 ;
        RECT 55.610 0.275 55.750 0.610 ;
        RECT 56.570 0.275 56.710 0.610 ;
        RECT 57.530 0.275 57.670 0.610 ;
        RECT 58.490 0.275 58.630 0.610 ;
        RECT 59.450 0.275 59.590 0.610 ;
        RECT 60.410 0.275 60.550 0.610 ;
        RECT 61.370 0.275 61.510 0.610 ;
        RECT 62.330 0.275 62.470 0.610 ;
        RECT 63.290 0.275 63.430 0.610 ;
        RECT 64.250 0.275 64.390 0.610 ;
        RECT 65.210 0.275 65.350 0.610 ;
        RECT 66.170 0.275 66.310 0.610 ;
        RECT 67.130 0.275 67.270 0.610 ;
        RECT 68.090 0.275 68.230 0.610 ;
        RECT 69.050 0.275 69.190 0.610 ;
        RECT 70.010 0.275 70.150 0.610 ;
        RECT 70.970 0.275 71.110 0.610 ;
        RECT 71.930 0.275 72.070 0.610 ;
        RECT 72.890 0.275 73.030 0.610 ;
        RECT 73.850 0.275 73.990 0.610 ;
        RECT 74.810 0.275 74.950 0.610 ;
        RECT 75.770 0.275 75.910 0.610 ;
        RECT 76.730 0.275 76.870 0.610 ;
        RECT 77.690 0.275 77.830 0.610 ;
        RECT 78.650 0.275 78.790 0.610 ;
        RECT 79.610 0.275 79.750 0.610 ;
        RECT 80.570 0.275 80.710 0.610 ;
        RECT 81.530 0.275 81.670 0.610 ;
        RECT 82.490 0.275 82.630 0.610 ;
        RECT 83.450 0.275 83.590 0.610 ;
        RECT 84.410 0.275 84.550 0.610 ;
        RECT 85.370 0.275 85.510 0.610 ;
        RECT 86.330 0.275 86.470 0.610 ;
        RECT 87.290 0.275 87.430 0.610 ;
        RECT 88.250 0.275 88.390 0.610 ;
        RECT 89.210 0.275 89.350 0.610 ;
        RECT 90.170 0.275 90.310 0.610 ;
        RECT 91.130 0.275 91.270 0.610 ;
        RECT 92.090 0.275 92.230 0.610 ;
        RECT 93.050 0.275 93.190 0.610 ;
        RECT 94.010 0.275 94.150 0.610 ;
        RECT 94.970 0.275 95.110 0.610 ;
        RECT 95.930 0.275 96.070 0.610 ;
        RECT 96.890 0.275 97.030 0.610 ;
        RECT 97.850 0.275 97.990 0.610 ;
        RECT 98.810 0.275 98.950 0.610 ;
        RECT 99.770 0.275 99.910 0.610 ;
        RECT 100.730 0.275 100.870 0.610 ;
        RECT 101.690 0.275 101.830 0.610 ;
        RECT 102.650 0.275 102.790 0.610 ;
        RECT 103.610 0.275 103.750 0.610 ;
        RECT 104.570 0.275 104.710 0.610 ;
        RECT 105.530 0.275 105.670 0.610 ;
        RECT 106.490 0.275 106.630 0.610 ;
        RECT 107.450 0.275 107.590 0.610 ;
        RECT 108.410 0.275 108.550 0.610 ;
        RECT 109.370 0.275 109.510 0.610 ;
        RECT 110.330 0.275 110.470 0.610 ;
        RECT 111.290 0.275 111.430 0.610 ;
        RECT 112.250 0.275 112.390 0.610 ;
        RECT 113.210 0.275 113.350 0.610 ;
        RECT 114.170 0.275 114.310 0.610 ;
        RECT 115.130 0.275 115.270 0.610 ;
        RECT 116.090 0.275 116.230 0.610 ;
        RECT 117.050 0.275 117.190 0.610 ;
        RECT 118.010 0.275 118.150 0.610 ;
        RECT 118.970 0.275 119.110 0.610 ;
        RECT 119.930 0.275 120.070 0.610 ;
        RECT 120.890 0.275 121.030 0.610 ;
        RECT 121.850 0.275 121.990 0.610 ;
        RECT 122.810 0.275 122.950 0.610 ;
        RECT 123.770 0.275 123.910 0.610 ;
        RECT 124.730 0.275 124.870 0.610 ;
        RECT 125.690 0.275 125.830 0.610 ;
        RECT 126.650 0.275 126.790 0.610 ;
        RECT 127.610 0.275 127.750 0.610 ;
        RECT 128.570 0.275 128.710 0.610 ;
        RECT 129.530 0.275 129.670 0.610 ;
        RECT 130.490 0.275 130.630 0.610 ;
        RECT 131.450 0.275 131.590 0.610 ;
        RECT 132.410 0.275 132.550 0.610 ;
        RECT 133.370 0.275 133.510 0.610 ;
        RECT 134.330 0.275 134.470 0.610 ;
        RECT 135.290 0.275 135.430 0.610 ;
        RECT 136.250 0.275 136.390 0.610 ;
        RECT 137.210 0.275 137.350 0.610 ;
        RECT 138.170 0.275 138.310 0.610 ;
        RECT 139.130 0.275 139.270 0.610 ;
        RECT 140.090 0.275 140.230 0.610 ;
        RECT 141.050 0.275 141.190 0.610 ;
        RECT 142.010 0.275 142.150 0.610 ;
        RECT 142.970 0.275 143.110 0.610 ;
        RECT 143.930 0.275 144.070 0.610 ;
        RECT 144.890 0.275 145.030 0.610 ;
        RECT 145.850 0.275 145.990 0.610 ;
        RECT 146.810 0.275 146.950 0.610 ;
        RECT 147.770 0.275 147.910 0.610 ;
        RECT 148.730 0.275 148.870 0.610 ;
        RECT 149.690 0.275 149.830 0.610 ;
        RECT 150.650 0.275 150.790 0.610 ;
        RECT 151.610 0.275 151.750 0.610 ;
        RECT 152.570 0.275 152.710 0.610 ;
        RECT 153.530 0.275 153.670 0.610 ;
        RECT 154.490 0.275 154.630 0.610 ;
        RECT 155.450 0.275 155.590 0.610 ;
        RECT 156.410 0.275 156.550 0.610 ;
        RECT 157.370 0.275 157.510 0.610 ;
        RECT 158.330 0.275 158.470 0.610 ;
        RECT 159.290 0.275 159.430 0.610 ;
        RECT 160.250 0.275 160.390 0.610 ;
        RECT 161.210 0.275 161.350 0.610 ;
        RECT 162.170 0.275 162.310 0.610 ;
        RECT 163.130 0.275 163.270 0.610 ;
        RECT 164.090 0.275 164.230 0.610 ;
        RECT 165.050 0.275 165.190 0.610 ;
        RECT 166.010 0.275 166.150 0.610 ;
        RECT 166.970 0.275 167.110 0.610 ;
        RECT 167.930 0.275 212.265 0.610 ;
      LAYER Metal3 ;
        RECT 0.610 52.090 214.430 52.600 ;
        RECT 0.380 51.230 214.640 52.090 ;
        RECT 0.610 50.410 214.430 51.230 ;
        RECT 0.380 49.550 214.640 50.410 ;
        RECT 0.610 48.730 214.430 49.550 ;
        RECT 0.380 47.870 214.640 48.730 ;
        RECT 0.610 47.050 214.430 47.870 ;
        RECT 0.380 46.190 214.640 47.050 ;
        RECT 0.610 45.370 214.430 46.190 ;
        RECT 0.380 44.510 214.640 45.370 ;
        RECT 0.610 43.690 214.430 44.510 ;
        RECT 0.380 42.830 214.640 43.690 ;
        RECT 0.610 42.010 214.430 42.830 ;
        RECT 0.380 41.150 214.640 42.010 ;
        RECT 0.610 40.330 214.430 41.150 ;
        RECT 0.380 39.470 214.640 40.330 ;
        RECT 0.610 38.650 214.430 39.470 ;
        RECT 0.380 37.790 214.640 38.650 ;
        RECT 0.610 36.970 214.430 37.790 ;
        RECT 0.380 36.110 214.640 36.970 ;
        RECT 0.610 35.290 214.430 36.110 ;
        RECT 0.380 34.430 214.640 35.290 ;
        RECT 0.610 33.610 214.430 34.430 ;
        RECT 0.380 32.750 214.640 33.610 ;
        RECT 0.610 31.930 214.430 32.750 ;
        RECT 0.380 31.070 214.640 31.930 ;
        RECT 0.610 30.250 214.430 31.070 ;
        RECT 0.380 29.390 214.640 30.250 ;
        RECT 0.610 28.570 214.430 29.390 ;
        RECT 0.380 27.710 214.640 28.570 ;
        RECT 0.610 26.890 214.430 27.710 ;
        RECT 0.380 26.030 214.640 26.890 ;
        RECT 0.610 25.210 214.430 26.030 ;
        RECT 0.380 24.350 214.640 25.210 ;
        RECT 0.610 23.530 214.430 24.350 ;
        RECT 0.380 22.670 214.640 23.530 ;
        RECT 0.610 21.850 214.430 22.670 ;
        RECT 0.380 20.990 214.640 21.850 ;
        RECT 0.610 20.170 214.430 20.990 ;
        RECT 0.380 19.310 214.640 20.170 ;
        RECT 0.610 18.490 214.430 19.310 ;
        RECT 0.380 17.630 214.640 18.490 ;
        RECT 0.610 16.810 214.430 17.630 ;
        RECT 0.380 15.950 214.640 16.810 ;
        RECT 0.610 15.130 214.430 15.950 ;
        RECT 0.380 14.270 214.640 15.130 ;
        RECT 0.610 13.450 214.430 14.270 ;
        RECT 0.380 12.590 214.640 13.450 ;
        RECT 0.610 11.770 214.430 12.590 ;
        RECT 0.380 10.910 214.640 11.770 ;
        RECT 0.610 10.090 214.430 10.910 ;
        RECT 0.380 9.230 214.640 10.090 ;
        RECT 0.610 8.410 214.430 9.230 ;
        RECT 0.380 7.550 214.640 8.410 ;
        RECT 0.610 6.730 214.430 7.550 ;
        RECT 0.380 5.870 214.640 6.730 ;
        RECT 0.610 5.050 214.430 5.870 ;
        RECT 0.380 4.190 214.640 5.050 ;
        RECT 0.610 3.370 214.430 4.190 ;
        RECT 0.380 2.510 214.640 3.370 ;
        RECT 0.610 1.690 214.430 2.510 ;
        RECT 0.380 0.830 214.640 1.690 ;
        RECT 0.610 0.315 214.430 0.830 ;
      LAYER Metal4 ;
        RECT 15.560 0.270 210.825 49.285 ;
      LAYER Metal5 ;
        RECT 15.515 0.320 210.865 49.450 ;
  END
END N_term_single
END LIBRARY

